VERSION 5.7 ;
  NOWIREEXTENSIONATPIN ON ;
  DIVIDERCHAR "/" ;
  BUSBITCHARS "[]" ;
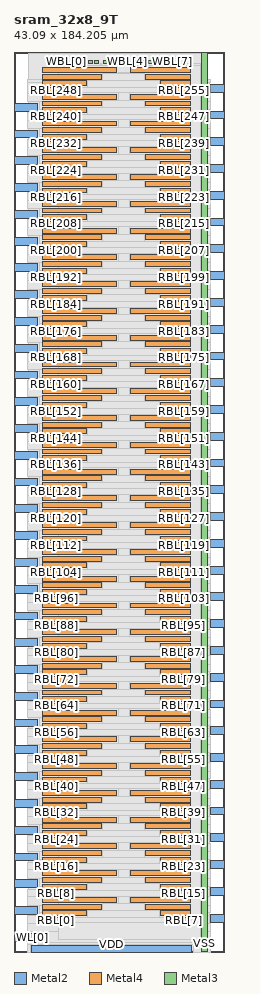
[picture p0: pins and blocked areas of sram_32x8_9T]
MACRO sram_32x8_9T
  CLASS BLOCK ;
  FOREIGN sram_32x8_9T ;
  ORIGIN -1.165 1.305 ;
  SIZE 43.090 BY 184.205 ;
  PIN A[0]
    PORT
      LAYER Metal2 ;
        RECT 41.420 4.820 44.255 6.415 ;
    END
  END A[0]
  PIN A[1]
    PORT
      LAYER Metal2 ;
        RECT 41.420 10.300 44.255 11.895 ;
    END
  END A[1]
  PIN A[2]
    PORT
      LAYER Metal2 ;
        RECT 41.420 15.780 44.255 17.375 ;
    END
  END A[2]
  PIN A[3]
    PORT
      LAYER Metal2 ;
        RECT 41.420 21.260 44.255 22.855 ;
    END
  END A[3]
  PIN A[4]
    PORT
      LAYER Metal2 ;
        RECT 41.420 26.740 44.255 28.335 ;
    END
  END A[4]
  PIN A[5]
    PORT
      LAYER Metal2 ;
        RECT 41.420 32.220 44.255 33.815 ;
    END
  END A[5]
  PIN A[6]
    PORT
      LAYER Metal2 ;
        RECT 41.420 37.700 44.255 39.295 ;
    END
  END A[6]
  PIN A[7]
    PORT
      LAYER Metal2 ;
        RECT 41.420 43.180 44.255 44.775 ;
    END
  END A[7]
  PIN A[8]
    PORT
      LAYER Metal2 ;
        RECT 41.420 48.660 44.255 50.255 ;
    END
  END A[8]
  PIN A[9]
    PORT
      LAYER Metal2 ;
        RECT 41.420 54.140 44.255 55.735 ;
    END
  END A[9]
  PIN A[10]
    PORT
      LAYER Metal2 ;
        RECT 41.420 59.620 44.255 61.215 ;
    END
  END A[10]
  PIN A[11]
    PORT
      LAYER Metal2 ;
        RECT 41.420 65.100 44.255 66.695 ;
    END
  END A[11]
  PIN A[12]
    PORT
      LAYER Metal2 ;
        RECT 41.420 70.580 44.255 72.175 ;
    END
  END A[12]
  PIN A[13]
    PORT
      LAYER Metal2 ;
        RECT 41.420 76.060 44.255 77.655 ;
    END
  END A[13]
  PIN A[14]
    PORT
      LAYER Metal2 ;
        RECT 41.420 81.540 44.255 83.135 ;
    END
  END A[14]
  PIN A[15]
    PORT
      LAYER Metal2 ;
        RECT 41.420 87.020 44.255 88.615 ;
    END
  END A[15]
  PIN A[16]
    PORT
      LAYER Metal2 ;
        RECT 41.420 92.500 44.255 94.095 ;
    END
  END A[16]
  PIN A[17]
    PORT
      LAYER Metal2 ;
        RECT 41.420 97.980 44.255 99.575 ;
    END
  END A[17]
  PIN A[18]
    PORT
      LAYER Metal2 ;
        RECT 41.420 103.460 44.255 105.055 ;
    END
  END A[18]
  PIN A[19]
    PORT
      LAYER Metal2 ;
        RECT 41.420 108.940 44.255 110.535 ;
    END
  END A[19]
  PIN A[20]
    PORT
      LAYER Metal2 ;
        RECT 41.420 114.420 44.255 116.015 ;
    END
  END A[20]
  PIN A[21]
    PORT
      LAYER Metal2 ;
        RECT 41.420 119.900 44.255 121.495 ;
    END
  END A[21]
  PIN A[22]
    PORT
      LAYER Metal2 ;
        RECT 41.420 125.380 44.255 126.975 ;
    END
  END A[22]
  PIN A[23]
    PORT
      LAYER Metal2 ;
        RECT 41.420 130.860 44.255 132.455 ;
    END
  END A[23]
  PIN A[24]
    PORT
      LAYER Metal2 ;
        RECT 41.420 136.340 44.255 137.935 ;
    END
  END A[24]
  PIN A[25]
    PORT
      LAYER Metal2 ;
        RECT 41.420 141.820 44.255 143.415 ;
    END
  END A[25]
  PIN A[26]
    PORT
      LAYER Metal2 ;
        RECT 41.420 147.300 44.255 148.895 ;
    END
  END A[26]
  PIN A[27]
    PORT
      LAYER Metal2 ;
        RECT 41.420 152.780 44.255 154.375 ;
    END
  END A[27]
  PIN A[28]
    PORT
      LAYER Metal2 ;
        RECT 41.420 158.260 44.255 159.855 ;
    END
  END A[28]
  PIN A[29]
    PORT
      LAYER Metal2 ;
        RECT 41.420 163.740 44.255 165.335 ;
    END
  END A[29]
  PIN A[30]
    PORT
      LAYER Metal2 ;
        RECT 41.420 169.220 44.255 170.815 ;
    END
  END A[30]
  PIN A[31]
    PORT
      LAYER Metal2 ;
        RECT 41.420 174.700 44.255 176.295 ;
    END
  END A[31]
  PIN RBL[0]
    ANTENNADIFFAREA 0.511400 ;
    PORT
      LAYER Metal4 ;
        RECT 7.045 4.730 12.555 5.730 ;
    END
  END RBL[0]
  PIN RBL[1]
    ANTENNADIFFAREA 0.511400 ;
    PORT
      LAYER Metal4 ;
        RECT 7.045 6.100 15.955 7.100 ;
    END
  END RBL[1]
  PIN RBL[2]
    ANTENNADIFFAREA 0.511400 ;
    PORT
      LAYER Metal4 ;
        RECT 7.045 7.470 19.065 8.470 ;
    END
  END RBL[2]
  PIN RBL[3]
    ANTENNADIFFAREA 0.511400 ;
    PORT
      LAYER Metal4 ;
        RECT 7.045 8.840 22.175 9.840 ;
    END
  END RBL[3]
  PIN RBL[4]
    ANTENNADIFFAREA 0.511400 ;
    PORT
      LAYER Metal4 ;
        RECT 25.005 8.840 37.380 9.840 ;
    END
  END RBL[4]
  PIN RBL[5]
    ANTENNADIFFAREA 0.511400 ;
    PORT
      LAYER Metal4 ;
        RECT 28.115 7.470 37.380 8.470 ;
    END
  END RBL[5]
  PIN RBL[6]
    ANTENNADIFFAREA 0.511400 ;
    PORT
      LAYER Metal4 ;
        RECT 31.225 6.100 37.380 7.100 ;
    END
  END RBL[6]
  PIN RBL[7]
    ANTENNADIFFAREA 0.511400 ;
    PORT
      LAYER Metal4 ;
        RECT 34.335 4.730 37.380 5.730 ;
    END
  END RBL[7]
  PIN RBL[8]
    ANTENNADIFFAREA 0.511400 ;
    PORT
      LAYER Metal4 ;
        RECT 7.045 10.210 12.555 11.210 ;
    END
  END RBL[8]
  PIN RBL[9]
    ANTENNADIFFAREA 0.511400 ;
    PORT
      LAYER Metal4 ;
        RECT 7.045 11.580 15.955 12.580 ;
    END
  END RBL[9]
  PIN RBL[10]
    ANTENNADIFFAREA 0.511400 ;
    PORT
      LAYER Metal4 ;
        RECT 7.045 12.950 19.065 13.950 ;
    END
  END RBL[10]
  PIN RBL[11]
    ANTENNADIFFAREA 0.511400 ;
    PORT
      LAYER Metal4 ;
        RECT 7.045 14.320 22.175 15.320 ;
    END
  END RBL[11]
  PIN RBL[12]
    ANTENNADIFFAREA 0.511400 ;
    PORT
      LAYER Metal4 ;
        RECT 25.005 14.320 37.380 15.320 ;
    END
  END RBL[12]
  PIN RBL[13]
    ANTENNADIFFAREA 0.511400 ;
    PORT
      LAYER Metal4 ;
        RECT 28.115 12.950 37.380 13.950 ;
    END
  END RBL[13]
  PIN RBL[14]
    ANTENNADIFFAREA 0.511400 ;
    PORT
      LAYER Metal4 ;
        RECT 31.225 11.580 37.380 12.580 ;
    END
  END RBL[14]
  PIN RBL[15]
    ANTENNADIFFAREA 0.511400 ;
    PORT
      LAYER Metal4 ;
        RECT 34.335 10.210 37.380 11.210 ;
    END
  END RBL[15]
  PIN RBL[16]
    ANTENNADIFFAREA 0.511400 ;
    PORT
      LAYER Metal4 ;
        RECT 7.045 15.690 12.555 16.690 ;
    END
  END RBL[16]
  PIN RBL[17]
    ANTENNADIFFAREA 0.511400 ;
    PORT
      LAYER Metal4 ;
        RECT 7.045 17.060 15.955 18.060 ;
    END
  END RBL[17]
  PIN RBL[18]
    ANTENNADIFFAREA 0.511400 ;
    PORT
      LAYER Metal4 ;
        RECT 7.045 18.430 19.065 19.430 ;
    END
  END RBL[18]
  PIN RBL[19]
    ANTENNADIFFAREA 0.511400 ;
    PORT
      LAYER Metal4 ;
        RECT 7.045 19.800 22.175 20.800 ;
    END
  END RBL[19]
  PIN RBL[20]
    ANTENNADIFFAREA 0.511400 ;
    PORT
      LAYER Metal4 ;
        RECT 25.005 19.800 37.380 20.800 ;
    END
  END RBL[20]
  PIN RBL[21]
    ANTENNADIFFAREA 0.511400 ;
    PORT
      LAYER Metal4 ;
        RECT 28.115 18.430 37.380 19.430 ;
    END
  END RBL[21]
  PIN RBL[22]
    ANTENNADIFFAREA 0.511400 ;
    PORT
      LAYER Metal4 ;
        RECT 31.225 17.060 37.380 18.060 ;
    END
  END RBL[22]
  PIN RBL[23]
    ANTENNADIFFAREA 0.511400 ;
    PORT
      LAYER Metal4 ;
        RECT 34.335 15.690 37.380 16.690 ;
    END
  END RBL[23]
  PIN RBL[24]
    ANTENNADIFFAREA 0.511400 ;
    PORT
      LAYER Metal4 ;
        RECT 7.045 21.170 12.555 22.170 ;
    END
  END RBL[24]
  PIN RBL[25]
    ANTENNADIFFAREA 0.511400 ;
    PORT
      LAYER Metal4 ;
        RECT 7.045 22.540 15.955 23.540 ;
    END
  END RBL[25]
  PIN RBL[26]
    ANTENNADIFFAREA 0.511400 ;
    PORT
      LAYER Metal4 ;
        RECT 7.045 23.910 19.065 24.910 ;
    END
  END RBL[26]
  PIN RBL[27]
    ANTENNADIFFAREA 0.511400 ;
    PORT
      LAYER Metal4 ;
        RECT 7.045 25.280 22.175 26.280 ;
    END
  END RBL[27]
  PIN RBL[28]
    ANTENNADIFFAREA 0.511400 ;
    PORT
      LAYER Metal4 ;
        RECT 25.005 25.280 37.380 26.280 ;
    END
  END RBL[28]
  PIN RBL[29]
    ANTENNADIFFAREA 0.511400 ;
    PORT
      LAYER Metal4 ;
        RECT 28.115 23.910 37.380 24.910 ;
    END
  END RBL[29]
  PIN RBL[30]
    ANTENNADIFFAREA 0.511400 ;
    PORT
      LAYER Metal4 ;
        RECT 31.225 22.540 37.380 23.540 ;
    END
  END RBL[30]
  PIN RBL[31]
    ANTENNADIFFAREA 0.511400 ;
    PORT
      LAYER Metal4 ;
        RECT 34.335 21.170 37.380 22.170 ;
    END
  END RBL[31]
  PIN RBL[32]
    ANTENNADIFFAREA 0.511400 ;
    PORT
      LAYER Metal4 ;
        RECT 7.045 26.650 12.555 27.650 ;
    END
  END RBL[32]
  PIN RBL[33]
    ANTENNADIFFAREA 0.511400 ;
    PORT
      LAYER Metal4 ;
        RECT 7.045 28.020 15.955 29.020 ;
    END
  END RBL[33]
  PIN RBL[34]
    ANTENNADIFFAREA 0.511400 ;
    PORT
      LAYER Metal4 ;
        RECT 7.045 29.390 19.065 30.390 ;
    END
  END RBL[34]
  PIN RBL[35]
    ANTENNADIFFAREA 0.511400 ;
    PORT
      LAYER Metal4 ;
        RECT 7.045 30.760 22.175 31.760 ;
    END
  END RBL[35]
  PIN RBL[36]
    ANTENNADIFFAREA 0.511400 ;
    PORT
      LAYER Metal4 ;
        RECT 25.005 30.760 37.380 31.760 ;
    END
  END RBL[36]
  PIN RBL[37]
    ANTENNADIFFAREA 0.511400 ;
    PORT
      LAYER Metal4 ;
        RECT 28.115 29.390 37.380 30.390 ;
    END
  END RBL[37]
  PIN RBL[38]
    ANTENNADIFFAREA 0.511400 ;
    PORT
      LAYER Metal4 ;
        RECT 31.225 28.020 37.380 29.020 ;
    END
  END RBL[38]
  PIN RBL[39]
    ANTENNADIFFAREA 0.511400 ;
    PORT
      LAYER Metal4 ;
        RECT 34.335 26.650 37.380 27.650 ;
    END
  END RBL[39]
  PIN RBL[40]
    ANTENNADIFFAREA 0.511400 ;
    PORT
      LAYER Metal4 ;
        RECT 7.045 32.130 12.555 33.130 ;
    END
  END RBL[40]
  PIN RBL[41]
    ANTENNADIFFAREA 0.511400 ;
    PORT
      LAYER Metal4 ;
        RECT 7.045 33.500 15.955 34.500 ;
    END
  END RBL[41]
  PIN RBL[42]
    ANTENNADIFFAREA 0.511400 ;
    PORT
      LAYER Metal4 ;
        RECT 7.045 34.870 19.065 35.870 ;
    END
  END RBL[42]
  PIN RBL[43]
    ANTENNADIFFAREA 0.511400 ;
    PORT
      LAYER Metal4 ;
        RECT 7.045 36.240 22.175 37.240 ;
    END
  END RBL[43]
  PIN RBL[44]
    ANTENNADIFFAREA 0.511400 ;
    PORT
      LAYER Metal4 ;
        RECT 25.005 36.240 37.380 37.240 ;
    END
  END RBL[44]
  PIN RBL[45]
    ANTENNADIFFAREA 0.511400 ;
    PORT
      LAYER Metal4 ;
        RECT 28.115 34.870 37.380 35.870 ;
    END
  END RBL[45]
  PIN RBL[46]
    ANTENNADIFFAREA 0.511400 ;
    PORT
      LAYER Metal4 ;
        RECT 31.225 33.500 37.380 34.500 ;
    END
  END RBL[46]
  PIN RBL[47]
    ANTENNADIFFAREA 0.511400 ;
    PORT
      LAYER Metal4 ;
        RECT 34.335 32.130 37.380 33.130 ;
    END
  END RBL[47]
  PIN RBL[48]
    ANTENNADIFFAREA 0.511400 ;
    PORT
      LAYER Metal4 ;
        RECT 7.045 37.610 12.555 38.610 ;
    END
  END RBL[48]
  PIN RBL[49]
    ANTENNADIFFAREA 0.511400 ;
    PORT
      LAYER Metal4 ;
        RECT 7.045 38.980 15.955 39.980 ;
    END
  END RBL[49]
  PIN RBL[50]
    ANTENNADIFFAREA 0.511400 ;
    PORT
      LAYER Metal4 ;
        RECT 7.045 40.350 19.065 41.350 ;
    END
  END RBL[50]
  PIN RBL[51]
    ANTENNADIFFAREA 0.511400 ;
    PORT
      LAYER Metal4 ;
        RECT 7.045 41.720 22.175 42.720 ;
    END
  END RBL[51]
  PIN RBL[52]
    ANTENNADIFFAREA 0.511400 ;
    PORT
      LAYER Metal4 ;
        RECT 25.005 41.720 37.380 42.720 ;
    END
  END RBL[52]
  PIN RBL[53]
    ANTENNADIFFAREA 0.511400 ;
    PORT
      LAYER Metal4 ;
        RECT 28.115 40.350 37.380 41.350 ;
    END
  END RBL[53]
  PIN RBL[54]
    ANTENNADIFFAREA 0.511400 ;
    PORT
      LAYER Metal4 ;
        RECT 31.225 38.980 37.380 39.980 ;
    END
  END RBL[54]
  PIN RBL[55]
    ANTENNADIFFAREA 0.511400 ;
    PORT
      LAYER Metal4 ;
        RECT 34.335 37.610 37.380 38.610 ;
    END
  END RBL[55]
  PIN RBL[56]
    ANTENNADIFFAREA 0.511400 ;
    PORT
      LAYER Metal4 ;
        RECT 7.045 43.090 12.555 44.090 ;
    END
  END RBL[56]
  PIN RBL[57]
    ANTENNADIFFAREA 0.511400 ;
    PORT
      LAYER Metal4 ;
        RECT 7.045 44.460 15.955 45.460 ;
    END
  END RBL[57]
  PIN RBL[58]
    ANTENNADIFFAREA 0.511400 ;
    PORT
      LAYER Metal4 ;
        RECT 7.045 45.830 19.065 46.830 ;
    END
  END RBL[58]
  PIN RBL[59]
    ANTENNADIFFAREA 0.511400 ;
    PORT
      LAYER Metal4 ;
        RECT 7.045 47.200 22.175 48.200 ;
    END
  END RBL[59]
  PIN RBL[60]
    ANTENNADIFFAREA 0.511400 ;
    PORT
      LAYER Metal4 ;
        RECT 25.005 47.200 37.380 48.200 ;
    END
  END RBL[60]
  PIN RBL[61]
    ANTENNADIFFAREA 0.511400 ;
    PORT
      LAYER Metal4 ;
        RECT 28.115 45.830 37.380 46.830 ;
    END
  END RBL[61]
  PIN RBL[62]
    ANTENNADIFFAREA 0.511400 ;
    PORT
      LAYER Metal4 ;
        RECT 31.225 44.460 37.380 45.460 ;
    END
  END RBL[62]
  PIN RBL[63]
    ANTENNADIFFAREA 0.511400 ;
    PORT
      LAYER Metal4 ;
        RECT 34.335 43.090 37.380 44.090 ;
    END
  END RBL[63]
  PIN RBL[64]
    ANTENNADIFFAREA 0.511400 ;
    PORT
      LAYER Metal4 ;
        RECT 7.045 48.570 12.555 49.570 ;
    END
  END RBL[64]
  PIN RBL[65]
    ANTENNADIFFAREA 0.511400 ;
    PORT
      LAYER Metal4 ;
        RECT 7.045 49.940 15.955 50.940 ;
    END
  END RBL[65]
  PIN RBL[66]
    ANTENNADIFFAREA 0.511400 ;
    PORT
      LAYER Metal4 ;
        RECT 7.045 51.310 19.065 52.310 ;
    END
  END RBL[66]
  PIN RBL[67]
    ANTENNADIFFAREA 0.511400 ;
    PORT
      LAYER Metal4 ;
        RECT 7.045 52.680 22.175 53.680 ;
    END
  END RBL[67]
  PIN RBL[68]
    ANTENNADIFFAREA 0.511400 ;
    PORT
      LAYER Metal4 ;
        RECT 25.005 52.680 37.380 53.680 ;
    END
  END RBL[68]
  PIN RBL[69]
    ANTENNADIFFAREA 0.511400 ;
    PORT
      LAYER Metal4 ;
        RECT 28.115 51.310 37.380 52.310 ;
    END
  END RBL[69]
  PIN RBL[70]
    ANTENNADIFFAREA 0.511400 ;
    PORT
      LAYER Metal4 ;
        RECT 31.225 49.940 37.380 50.940 ;
    END
  END RBL[70]
  PIN RBL[71]
    ANTENNADIFFAREA 0.511400 ;
    PORT
      LAYER Metal4 ;
        RECT 34.335 48.570 37.380 49.570 ;
    END
  END RBL[71]
  PIN RBL[72]
    ANTENNADIFFAREA 0.511400 ;
    PORT
      LAYER Metal4 ;
        RECT 7.045 54.050 12.555 55.050 ;
    END
  END RBL[72]
  PIN RBL[73]
    ANTENNADIFFAREA 0.511400 ;
    PORT
      LAYER Metal4 ;
        RECT 7.045 55.420 15.955 56.420 ;
    END
  END RBL[73]
  PIN RBL[74]
    ANTENNADIFFAREA 0.511400 ;
    PORT
      LAYER Metal4 ;
        RECT 7.045 56.790 19.065 57.790 ;
    END
  END RBL[74]
  PIN RBL[75]
    ANTENNADIFFAREA 0.511400 ;
    PORT
      LAYER Metal4 ;
        RECT 7.045 58.160 22.175 59.160 ;
    END
  END RBL[75]
  PIN RBL[76]
    ANTENNADIFFAREA 0.511400 ;
    PORT
      LAYER Metal4 ;
        RECT 25.005 58.160 37.380 59.160 ;
    END
  END RBL[76]
  PIN RBL[77]
    ANTENNADIFFAREA 0.511400 ;
    PORT
      LAYER Metal4 ;
        RECT 28.115 56.790 37.380 57.790 ;
    END
  END RBL[77]
  PIN RBL[78]
    ANTENNADIFFAREA 0.511400 ;
    PORT
      LAYER Metal4 ;
        RECT 31.225 55.420 37.380 56.420 ;
    END
  END RBL[78]
  PIN RBL[79]
    ANTENNADIFFAREA 0.511400 ;
    PORT
      LAYER Metal4 ;
        RECT 34.335 54.050 37.380 55.050 ;
    END
  END RBL[79]
  PIN RBL[80]
    ANTENNADIFFAREA 0.511400 ;
    PORT
      LAYER Metal4 ;
        RECT 7.045 59.530 12.555 60.530 ;
    END
  END RBL[80]
  PIN RBL[81]
    ANTENNADIFFAREA 0.511400 ;
    PORT
      LAYER Metal4 ;
        RECT 7.045 60.900 15.955 61.900 ;
    END
  END RBL[81]
  PIN RBL[82]
    ANTENNADIFFAREA 0.511400 ;
    PORT
      LAYER Metal4 ;
        RECT 7.045 62.270 19.065 63.270 ;
    END
  END RBL[82]
  PIN RBL[83]
    ANTENNADIFFAREA 0.511400 ;
    PORT
      LAYER Metal4 ;
        RECT 7.045 63.640 22.175 64.640 ;
    END
  END RBL[83]
  PIN RBL[84]
    ANTENNADIFFAREA 0.511400 ;
    PORT
      LAYER Metal4 ;
        RECT 25.005 63.640 37.380 64.640 ;
    END
  END RBL[84]
  PIN RBL[85]
    ANTENNADIFFAREA 0.511400 ;
    PORT
      LAYER Metal4 ;
        RECT 28.115 62.270 37.380 63.270 ;
    END
  END RBL[85]
  PIN RBL[86]
    ANTENNADIFFAREA 0.511400 ;
    PORT
      LAYER Metal4 ;
        RECT 31.225 60.900 37.380 61.900 ;
    END
  END RBL[86]
  PIN RBL[87]
    ANTENNADIFFAREA 0.511400 ;
    PORT
      LAYER Metal4 ;
        RECT 34.335 59.530 37.380 60.530 ;
    END
  END RBL[87]
  PIN RBL[88]
    ANTENNADIFFAREA 0.511400 ;
    PORT
      LAYER Metal4 ;
        RECT 7.045 65.010 12.555 66.010 ;
    END
  END RBL[88]
  PIN RBL[89]
    ANTENNADIFFAREA 0.511400 ;
    PORT
      LAYER Metal4 ;
        RECT 7.045 66.380 15.955 67.380 ;
    END
  END RBL[89]
  PIN RBL[90]
    ANTENNADIFFAREA 0.511400 ;
    PORT
      LAYER Metal4 ;
        RECT 7.045 67.750 19.065 68.750 ;
    END
  END RBL[90]
  PIN RBL[91]
    ANTENNADIFFAREA 0.511400 ;
    PORT
      LAYER Metal4 ;
        RECT 7.045 69.120 22.175 70.120 ;
    END
  END RBL[91]
  PIN RBL[92]
    ANTENNADIFFAREA 0.511400 ;
    PORT
      LAYER Metal4 ;
        RECT 25.005 69.120 37.380 70.120 ;
    END
  END RBL[92]
  PIN RBL[93]
    ANTENNADIFFAREA 0.511400 ;
    PORT
      LAYER Metal4 ;
        RECT 28.115 67.750 37.380 68.750 ;
    END
  END RBL[93]
  PIN RBL[94]
    ANTENNADIFFAREA 0.511400 ;
    PORT
      LAYER Metal4 ;
        RECT 31.225 66.380 37.380 67.380 ;
    END
  END RBL[94]
  PIN RBL[95]
    ANTENNADIFFAREA 0.511400 ;
    PORT
      LAYER Metal4 ;
        RECT 34.335 65.010 37.380 66.010 ;
    END
  END RBL[95]
  PIN RBL[96]
    ANTENNADIFFAREA 0.511400 ;
    PORT
      LAYER Metal4 ;
        RECT 7.045 70.490 12.555 71.490 ;
    END
  END RBL[96]
  PIN RBL[97]
    ANTENNADIFFAREA 0.511400 ;
    PORT
      LAYER Metal4 ;
        RECT 7.045 71.860 15.955 72.860 ;
    END
  END RBL[97]
  PIN RBL[98]
    ANTENNADIFFAREA 0.511400 ;
    PORT
      LAYER Metal4 ;
        RECT 7.045 73.230 19.065 74.230 ;
    END
  END RBL[98]
  PIN RBL[99]
    ANTENNADIFFAREA 0.511400 ;
    PORT
      LAYER Metal4 ;
        RECT 7.045 74.600 22.175 75.600 ;
    END
  END RBL[99]
  PIN RBL[100]
    ANTENNADIFFAREA 0.511400 ;
    PORT
      LAYER Metal4 ;
        RECT 25.005 74.600 37.380 75.600 ;
    END
  END RBL[100]
  PIN RBL[101]
    ANTENNADIFFAREA 0.511400 ;
    PORT
      LAYER Metal4 ;
        RECT 28.115 73.230 37.380 74.230 ;
    END
  END RBL[101]
  PIN RBL[102]
    ANTENNADIFFAREA 0.511400 ;
    PORT
      LAYER Metal4 ;
        RECT 31.225 71.860 37.380 72.860 ;
    END
  END RBL[102]
  PIN RBL[103]
    ANTENNADIFFAREA 0.511400 ;
    PORT
      LAYER Metal4 ;
        RECT 34.335 70.490 37.380 71.490 ;
    END
  END RBL[103]
  PIN RBL[104]
    ANTENNADIFFAREA 0.511400 ;
    PORT
      LAYER Metal4 ;
        RECT 7.045 75.970 12.555 76.970 ;
    END
  END RBL[104]
  PIN RBL[105]
    ANTENNADIFFAREA 0.511400 ;
    PORT
      LAYER Metal4 ;
        RECT 7.045 77.340 15.955 78.340 ;
    END
  END RBL[105]
  PIN RBL[106]
    ANTENNADIFFAREA 0.511400 ;
    PORT
      LAYER Metal4 ;
        RECT 7.045 78.710 19.065 79.710 ;
    END
  END RBL[106]
  PIN RBL[107]
    ANTENNADIFFAREA 0.511400 ;
    PORT
      LAYER Metal4 ;
        RECT 7.045 80.080 22.175 81.080 ;
    END
  END RBL[107]
  PIN RBL[108]
    ANTENNADIFFAREA 0.511400 ;
    PORT
      LAYER Metal4 ;
        RECT 25.005 80.080 37.380 81.080 ;
    END
  END RBL[108]
  PIN RBL[109]
    ANTENNADIFFAREA 0.511400 ;
    PORT
      LAYER Metal4 ;
        RECT 28.115 78.710 37.380 79.710 ;
    END
  END RBL[109]
  PIN RBL[110]
    ANTENNADIFFAREA 0.511400 ;
    PORT
      LAYER Metal4 ;
        RECT 31.225 77.340 37.380 78.340 ;
    END
  END RBL[110]
  PIN RBL[111]
    ANTENNADIFFAREA 0.511400 ;
    PORT
      LAYER Metal4 ;
        RECT 34.335 75.970 37.380 76.970 ;
    END
  END RBL[111]
  PIN RBL[112]
    ANTENNADIFFAREA 0.511400 ;
    PORT
      LAYER Metal4 ;
        RECT 7.045 81.450 12.555 82.450 ;
    END
  END RBL[112]
  PIN RBL[113]
    ANTENNADIFFAREA 0.511400 ;
    PORT
      LAYER Metal4 ;
        RECT 7.045 82.820 15.955 83.820 ;
    END
  END RBL[113]
  PIN RBL[114]
    ANTENNADIFFAREA 0.511400 ;
    PORT
      LAYER Metal4 ;
        RECT 7.045 84.190 19.065 85.190 ;
    END
  END RBL[114]
  PIN RBL[115]
    ANTENNADIFFAREA 0.511400 ;
    PORT
      LAYER Metal4 ;
        RECT 7.045 85.560 22.175 86.560 ;
    END
  END RBL[115]
  PIN RBL[116]
    ANTENNADIFFAREA 0.511400 ;
    PORT
      LAYER Metal4 ;
        RECT 25.005 85.560 37.380 86.560 ;
    END
  END RBL[116]
  PIN RBL[117]
    ANTENNADIFFAREA 0.511400 ;
    PORT
      LAYER Metal4 ;
        RECT 28.115 84.190 37.380 85.190 ;
    END
  END RBL[117]
  PIN RBL[118]
    ANTENNADIFFAREA 0.511400 ;
    PORT
      LAYER Metal4 ;
        RECT 31.225 82.820 37.380 83.820 ;
    END
  END RBL[118]
  PIN RBL[119]
    ANTENNADIFFAREA 0.511400 ;
    PORT
      LAYER Metal4 ;
        RECT 34.335 81.450 37.380 82.450 ;
    END
  END RBL[119]
  PIN RBL[120]
    ANTENNADIFFAREA 0.511400 ;
    PORT
      LAYER Metal4 ;
        RECT 7.045 86.930 12.555 87.930 ;
    END
  END RBL[120]
  PIN RBL[121]
    ANTENNADIFFAREA 0.511400 ;
    PORT
      LAYER Metal4 ;
        RECT 7.045 88.300 15.955 89.300 ;
    END
  END RBL[121]
  PIN RBL[122]
    ANTENNADIFFAREA 0.511400 ;
    PORT
      LAYER Metal4 ;
        RECT 7.045 89.670 19.065 90.670 ;
    END
  END RBL[122]
  PIN RBL[123]
    ANTENNADIFFAREA 0.511400 ;
    PORT
      LAYER Metal4 ;
        RECT 7.045 91.040 22.175 92.040 ;
    END
  END RBL[123]
  PIN RBL[124]
    ANTENNADIFFAREA 0.511400 ;
    PORT
      LAYER Metal4 ;
        RECT 25.005 91.040 37.380 92.040 ;
    END
  END RBL[124]
  PIN RBL[125]
    ANTENNADIFFAREA 0.511400 ;
    PORT
      LAYER Metal4 ;
        RECT 28.115 89.670 37.380 90.670 ;
    END
  END RBL[125]
  PIN RBL[126]
    ANTENNADIFFAREA 0.511400 ;
    PORT
      LAYER Metal4 ;
        RECT 31.225 88.300 37.380 89.300 ;
    END
  END RBL[126]
  PIN RBL[127]
    ANTENNADIFFAREA 0.511400 ;
    PORT
      LAYER Metal4 ;
        RECT 34.335 86.930 37.380 87.930 ;
    END
  END RBL[127]
  PIN RBL[128]
    ANTENNADIFFAREA 0.511400 ;
    PORT
      LAYER Metal4 ;
        RECT 7.045 92.410 12.555 93.410 ;
    END
  END RBL[128]
  PIN RBL[129]
    ANTENNADIFFAREA 0.511400 ;
    PORT
      LAYER Metal4 ;
        RECT 7.045 93.780 15.955 94.780 ;
    END
  END RBL[129]
  PIN RBL[130]
    ANTENNADIFFAREA 0.511400 ;
    PORT
      LAYER Metal4 ;
        RECT 7.045 95.150 19.065 96.150 ;
    END
  END RBL[130]
  PIN RBL[131]
    ANTENNADIFFAREA 0.511400 ;
    PORT
      LAYER Metal4 ;
        RECT 7.045 96.520 22.175 97.520 ;
    END
  END RBL[131]
  PIN RBL[132]
    ANTENNADIFFAREA 0.511400 ;
    PORT
      LAYER Metal4 ;
        RECT 25.005 96.520 37.380 97.520 ;
    END
  END RBL[132]
  PIN RBL[133]
    ANTENNADIFFAREA 0.511400 ;
    PORT
      LAYER Metal4 ;
        RECT 28.115 95.150 37.380 96.150 ;
    END
  END RBL[133]
  PIN RBL[134]
    ANTENNADIFFAREA 0.511400 ;
    PORT
      LAYER Metal4 ;
        RECT 31.225 93.780 37.380 94.780 ;
    END
  END RBL[134]
  PIN RBL[135]
    ANTENNADIFFAREA 0.511400 ;
    PORT
      LAYER Metal4 ;
        RECT 34.335 92.410 37.380 93.410 ;
    END
  END RBL[135]
  PIN RBL[136]
    ANTENNADIFFAREA 0.511400 ;
    PORT
      LAYER Metal4 ;
        RECT 7.045 97.890 12.555 98.890 ;
    END
  END RBL[136]
  PIN RBL[137]
    ANTENNADIFFAREA 0.511400 ;
    PORT
      LAYER Metal4 ;
        RECT 7.045 99.260 15.955 100.260 ;
    END
  END RBL[137]
  PIN RBL[138]
    ANTENNADIFFAREA 0.511400 ;
    PORT
      LAYER Metal4 ;
        RECT 7.045 100.630 19.065 101.630 ;
    END
  END RBL[138]
  PIN RBL[139]
    ANTENNADIFFAREA 0.511400 ;
    PORT
      LAYER Metal4 ;
        RECT 7.045 102.000 22.175 103.000 ;
    END
  END RBL[139]
  PIN RBL[140]
    ANTENNADIFFAREA 0.511400 ;
    PORT
      LAYER Metal4 ;
        RECT 25.005 102.000 37.380 103.000 ;
    END
  END RBL[140]
  PIN RBL[141]
    ANTENNADIFFAREA 0.511400 ;
    PORT
      LAYER Metal4 ;
        RECT 28.115 100.630 37.380 101.630 ;
    END
  END RBL[141]
  PIN RBL[142]
    ANTENNADIFFAREA 0.511400 ;
    PORT
      LAYER Metal4 ;
        RECT 31.225 99.260 37.380 100.260 ;
    END
  END RBL[142]
  PIN RBL[143]
    ANTENNADIFFAREA 0.511400 ;
    PORT
      LAYER Metal4 ;
        RECT 34.335 97.890 37.380 98.890 ;
    END
  END RBL[143]
  PIN RBL[144]
    ANTENNADIFFAREA 0.511400 ;
    PORT
      LAYER Metal4 ;
        RECT 7.045 103.370 12.555 104.370 ;
    END
  END RBL[144]
  PIN RBL[145]
    ANTENNADIFFAREA 0.511400 ;
    PORT
      LAYER Metal4 ;
        RECT 7.045 104.740 15.955 105.740 ;
    END
  END RBL[145]
  PIN RBL[146]
    ANTENNADIFFAREA 0.511400 ;
    PORT
      LAYER Metal4 ;
        RECT 7.045 106.110 19.065 107.110 ;
    END
  END RBL[146]
  PIN RBL[147]
    ANTENNADIFFAREA 0.511400 ;
    PORT
      LAYER Metal4 ;
        RECT 7.045 107.480 22.175 108.480 ;
    END
  END RBL[147]
  PIN RBL[148]
    ANTENNADIFFAREA 0.511400 ;
    PORT
      LAYER Metal4 ;
        RECT 25.005 107.480 37.380 108.480 ;
    END
  END RBL[148]
  PIN RBL[149]
    ANTENNADIFFAREA 0.511400 ;
    PORT
      LAYER Metal4 ;
        RECT 28.115 106.110 37.380 107.110 ;
    END
  END RBL[149]
  PIN RBL[150]
    ANTENNADIFFAREA 0.511400 ;
    PORT
      LAYER Metal4 ;
        RECT 31.225 104.740 37.380 105.740 ;
    END
  END RBL[150]
  PIN RBL[151]
    ANTENNADIFFAREA 0.511400 ;
    PORT
      LAYER Metal4 ;
        RECT 34.335 103.370 37.380 104.370 ;
    END
  END RBL[151]
  PIN RBL[152]
    ANTENNADIFFAREA 0.511400 ;
    PORT
      LAYER Metal4 ;
        RECT 7.045 108.850 12.555 109.850 ;
    END
  END RBL[152]
  PIN RBL[153]
    ANTENNADIFFAREA 0.511400 ;
    PORT
      LAYER Metal4 ;
        RECT 7.045 110.220 15.955 111.220 ;
    END
  END RBL[153]
  PIN RBL[154]
    ANTENNADIFFAREA 0.511400 ;
    PORT
      LAYER Metal4 ;
        RECT 7.045 111.590 19.065 112.590 ;
    END
  END RBL[154]
  PIN RBL[155]
    ANTENNADIFFAREA 0.511400 ;
    PORT
      LAYER Metal4 ;
        RECT 7.045 112.960 22.175 113.960 ;
    END
  END RBL[155]
  PIN RBL[156]
    ANTENNADIFFAREA 0.511400 ;
    PORT
      LAYER Metal4 ;
        RECT 25.005 112.960 37.380 113.960 ;
    END
  END RBL[156]
  PIN RBL[157]
    ANTENNADIFFAREA 0.511400 ;
    PORT
      LAYER Metal4 ;
        RECT 28.115 111.590 37.380 112.590 ;
    END
  END RBL[157]
  PIN RBL[158]
    ANTENNADIFFAREA 0.511400 ;
    PORT
      LAYER Metal4 ;
        RECT 31.225 110.220 37.380 111.220 ;
    END
  END RBL[158]
  PIN RBL[159]
    ANTENNADIFFAREA 0.511400 ;
    PORT
      LAYER Metal4 ;
        RECT 34.335 108.850 37.380 109.850 ;
    END
  END RBL[159]
  PIN RBL[160]
    ANTENNADIFFAREA 0.511400 ;
    PORT
      LAYER Metal4 ;
        RECT 7.045 114.330 12.555 115.330 ;
    END
  END RBL[160]
  PIN RBL[161]
    ANTENNADIFFAREA 0.511400 ;
    PORT
      LAYER Metal4 ;
        RECT 7.045 115.700 15.955 116.700 ;
    END
  END RBL[161]
  PIN RBL[162]
    ANTENNADIFFAREA 0.511400 ;
    PORT
      LAYER Metal4 ;
        RECT 7.045 117.070 19.065 118.070 ;
    END
  END RBL[162]
  PIN RBL[163]
    ANTENNADIFFAREA 0.511400 ;
    PORT
      LAYER Metal4 ;
        RECT 7.045 118.440 22.175 119.440 ;
    END
  END RBL[163]
  PIN RBL[164]
    ANTENNADIFFAREA 0.511400 ;
    PORT
      LAYER Metal4 ;
        RECT 25.005 118.440 37.380 119.440 ;
    END
  END RBL[164]
  PIN RBL[165]
    ANTENNADIFFAREA 0.511400 ;
    PORT
      LAYER Metal4 ;
        RECT 28.115 117.070 37.380 118.070 ;
    END
  END RBL[165]
  PIN RBL[166]
    ANTENNADIFFAREA 0.511400 ;
    PORT
      LAYER Metal4 ;
        RECT 31.225 115.700 37.380 116.700 ;
    END
  END RBL[166]
  PIN RBL[167]
    ANTENNADIFFAREA 0.511400 ;
    PORT
      LAYER Metal4 ;
        RECT 34.335 114.330 37.380 115.330 ;
    END
  END RBL[167]
  PIN RBL[168]
    ANTENNADIFFAREA 0.511400 ;
    PORT
      LAYER Metal4 ;
        RECT 7.045 119.810 12.555 120.810 ;
    END
  END RBL[168]
  PIN RBL[169]
    ANTENNADIFFAREA 0.511400 ;
    PORT
      LAYER Metal4 ;
        RECT 7.045 121.180 15.955 122.180 ;
    END
  END RBL[169]
  PIN RBL[170]
    ANTENNADIFFAREA 0.511400 ;
    PORT
      LAYER Metal4 ;
        RECT 7.045 122.550 19.065 123.550 ;
    END
  END RBL[170]
  PIN RBL[171]
    ANTENNADIFFAREA 0.511400 ;
    PORT
      LAYER Metal4 ;
        RECT 7.045 123.920 22.175 124.920 ;
    END
  END RBL[171]
  PIN RBL[172]
    ANTENNADIFFAREA 0.511400 ;
    PORT
      LAYER Metal4 ;
        RECT 25.005 123.920 37.380 124.920 ;
    END
  END RBL[172]
  PIN RBL[173]
    ANTENNADIFFAREA 0.511400 ;
    PORT
      LAYER Metal4 ;
        RECT 28.115 122.550 37.380 123.550 ;
    END
  END RBL[173]
  PIN RBL[174]
    ANTENNADIFFAREA 0.511400 ;
    PORT
      LAYER Metal4 ;
        RECT 31.225 121.180 37.380 122.180 ;
    END
  END RBL[174]
  PIN RBL[175]
    ANTENNADIFFAREA 0.511400 ;
    PORT
      LAYER Metal4 ;
        RECT 34.335 119.810 37.380 120.810 ;
    END
  END RBL[175]
  PIN RBL[176]
    ANTENNADIFFAREA 0.511400 ;
    PORT
      LAYER Metal4 ;
        RECT 7.045 125.290 12.555 126.290 ;
    END
  END RBL[176]
  PIN RBL[177]
    ANTENNADIFFAREA 0.511400 ;
    PORT
      LAYER Metal4 ;
        RECT 7.045 126.660 15.955 127.660 ;
    END
  END RBL[177]
  PIN RBL[178]
    ANTENNADIFFAREA 0.511400 ;
    PORT
      LAYER Metal4 ;
        RECT 7.045 128.030 19.065 129.030 ;
    END
  END RBL[178]
  PIN RBL[179]
    ANTENNADIFFAREA 0.511400 ;
    PORT
      LAYER Metal4 ;
        RECT 7.045 129.400 22.175 130.400 ;
    END
  END RBL[179]
  PIN RBL[180]
    ANTENNADIFFAREA 0.511400 ;
    PORT
      LAYER Metal4 ;
        RECT 25.005 129.400 37.380 130.400 ;
    END
  END RBL[180]
  PIN RBL[181]
    ANTENNADIFFAREA 0.511400 ;
    PORT
      LAYER Metal4 ;
        RECT 28.115 128.030 37.380 129.030 ;
    END
  END RBL[181]
  PIN RBL[182]
    ANTENNADIFFAREA 0.511400 ;
    PORT
      LAYER Metal4 ;
        RECT 31.225 126.660 37.380 127.660 ;
    END
  END RBL[182]
  PIN RBL[183]
    ANTENNADIFFAREA 0.511400 ;
    PORT
      LAYER Metal4 ;
        RECT 34.335 125.290 37.380 126.290 ;
    END
  END RBL[183]
  PIN RBL[184]
    ANTENNADIFFAREA 0.511400 ;
    PORT
      LAYER Metal4 ;
        RECT 7.045 130.770 12.555 131.770 ;
    END
  END RBL[184]
  PIN RBL[185]
    ANTENNADIFFAREA 0.511400 ;
    PORT
      LAYER Metal4 ;
        RECT 7.045 132.140 15.955 133.140 ;
    END
  END RBL[185]
  PIN RBL[186]
    ANTENNADIFFAREA 0.511400 ;
    PORT
      LAYER Metal4 ;
        RECT 7.045 133.510 19.065 134.510 ;
    END
  END RBL[186]
  PIN RBL[187]
    ANTENNADIFFAREA 0.511400 ;
    PORT
      LAYER Metal4 ;
        RECT 7.045 134.880 22.175 135.880 ;
    END
  END RBL[187]
  PIN RBL[188]
    ANTENNADIFFAREA 0.511400 ;
    PORT
      LAYER Metal4 ;
        RECT 25.005 134.880 37.380 135.880 ;
    END
  END RBL[188]
  PIN RBL[189]
    ANTENNADIFFAREA 0.511400 ;
    PORT
      LAYER Metal4 ;
        RECT 28.115 133.510 37.380 134.510 ;
    END
  END RBL[189]
  PIN RBL[190]
    ANTENNADIFFAREA 0.511400 ;
    PORT
      LAYER Metal4 ;
        RECT 31.225 132.140 37.380 133.140 ;
    END
  END RBL[190]
  PIN RBL[191]
    ANTENNADIFFAREA 0.511400 ;
    PORT
      LAYER Metal4 ;
        RECT 34.335 130.770 37.380 131.770 ;
    END
  END RBL[191]
  PIN RBL[192]
    ANTENNADIFFAREA 0.511400 ;
    PORT
      LAYER Metal4 ;
        RECT 7.045 136.250 12.555 137.250 ;
    END
  END RBL[192]
  PIN RBL[193]
    ANTENNADIFFAREA 0.511400 ;
    PORT
      LAYER Metal4 ;
        RECT 7.045 137.620 15.955 138.620 ;
    END
  END RBL[193]
  PIN RBL[194]
    ANTENNADIFFAREA 0.511400 ;
    PORT
      LAYER Metal4 ;
        RECT 7.045 138.990 19.065 139.990 ;
    END
  END RBL[194]
  PIN RBL[195]
    ANTENNADIFFAREA 0.511400 ;
    PORT
      LAYER Metal4 ;
        RECT 7.045 140.360 22.175 141.360 ;
    END
  END RBL[195]
  PIN RBL[196]
    ANTENNADIFFAREA 0.511400 ;
    PORT
      LAYER Metal4 ;
        RECT 25.005 140.360 37.380 141.360 ;
    END
  END RBL[196]
  PIN RBL[197]
    ANTENNADIFFAREA 0.511400 ;
    PORT
      LAYER Metal4 ;
        RECT 28.115 138.990 37.380 139.990 ;
    END
  END RBL[197]
  PIN RBL[198]
    ANTENNADIFFAREA 0.511400 ;
    PORT
      LAYER Metal4 ;
        RECT 31.225 137.620 37.380 138.620 ;
    END
  END RBL[198]
  PIN RBL[199]
    ANTENNADIFFAREA 0.511400 ;
    PORT
      LAYER Metal4 ;
        RECT 34.335 136.250 37.380 137.250 ;
    END
  END RBL[199]
  PIN RBL[200]
    ANTENNADIFFAREA 0.511400 ;
    PORT
      LAYER Metal4 ;
        RECT 7.045 141.730 12.555 142.730 ;
    END
  END RBL[200]
  PIN RBL[201]
    ANTENNADIFFAREA 0.511400 ;
    PORT
      LAYER Metal4 ;
        RECT 7.045 143.100 15.955 144.100 ;
    END
  END RBL[201]
  PIN RBL[202]
    ANTENNADIFFAREA 0.511400 ;
    PORT
      LAYER Metal4 ;
        RECT 7.045 144.470 19.065 145.470 ;
    END
  END RBL[202]
  PIN RBL[203]
    ANTENNADIFFAREA 0.511400 ;
    PORT
      LAYER Metal4 ;
        RECT 7.045 145.840 22.175 146.840 ;
    END
  END RBL[203]
  PIN RBL[204]
    ANTENNADIFFAREA 0.511400 ;
    PORT
      LAYER Metal4 ;
        RECT 25.005 145.840 37.380 146.840 ;
    END
  END RBL[204]
  PIN RBL[205]
    ANTENNADIFFAREA 0.511400 ;
    PORT
      LAYER Metal4 ;
        RECT 28.115 144.470 37.380 145.470 ;
    END
  END RBL[205]
  PIN RBL[206]
    ANTENNADIFFAREA 0.511400 ;
    PORT
      LAYER Metal4 ;
        RECT 31.225 143.100 37.380 144.100 ;
    END
  END RBL[206]
  PIN RBL[207]
    ANTENNADIFFAREA 0.511400 ;
    PORT
      LAYER Metal4 ;
        RECT 34.335 141.730 37.380 142.730 ;
    END
  END RBL[207]
  PIN RBL[208]
    ANTENNADIFFAREA 0.511400 ;
    PORT
      LAYER Metal4 ;
        RECT 7.045 147.210 12.555 148.210 ;
    END
  END RBL[208]
  PIN RBL[209]
    ANTENNADIFFAREA 0.511400 ;
    PORT
      LAYER Metal4 ;
        RECT 7.045 148.580 15.955 149.580 ;
    END
  END RBL[209]
  PIN RBL[210]
    ANTENNADIFFAREA 0.511400 ;
    PORT
      LAYER Metal4 ;
        RECT 7.045 149.950 19.065 150.950 ;
    END
  END RBL[210]
  PIN RBL[211]
    ANTENNADIFFAREA 0.511400 ;
    PORT
      LAYER Metal4 ;
        RECT 7.045 151.320 22.175 152.320 ;
    END
  END RBL[211]
  PIN RBL[212]
    ANTENNADIFFAREA 0.511400 ;
    PORT
      LAYER Metal4 ;
        RECT 25.005 151.320 37.380 152.320 ;
    END
  END RBL[212]
  PIN RBL[213]
    ANTENNADIFFAREA 0.511400 ;
    PORT
      LAYER Metal4 ;
        RECT 28.115 149.950 37.380 150.950 ;
    END
  END RBL[213]
  PIN RBL[214]
    ANTENNADIFFAREA 0.511400 ;
    PORT
      LAYER Metal4 ;
        RECT 31.225 148.580 37.380 149.580 ;
    END
  END RBL[214]
  PIN RBL[215]
    ANTENNADIFFAREA 0.511400 ;
    PORT
      LAYER Metal4 ;
        RECT 34.335 147.210 37.380 148.210 ;
    END
  END RBL[215]
  PIN RBL[216]
    ANTENNADIFFAREA 0.511400 ;
    PORT
      LAYER Metal4 ;
        RECT 7.045 152.690 12.555 153.690 ;
    END
  END RBL[216]
  PIN RBL[217]
    ANTENNADIFFAREA 0.511400 ;
    PORT
      LAYER Metal4 ;
        RECT 7.045 154.060 15.955 155.060 ;
    END
  END RBL[217]
  PIN RBL[218]
    ANTENNADIFFAREA 0.511400 ;
    PORT
      LAYER Metal4 ;
        RECT 7.045 155.430 19.065 156.430 ;
    END
  END RBL[218]
  PIN RBL[219]
    ANTENNADIFFAREA 0.511400 ;
    PORT
      LAYER Metal4 ;
        RECT 7.045 156.800 22.175 157.800 ;
    END
  END RBL[219]
  PIN RBL[220]
    ANTENNADIFFAREA 0.511400 ;
    PORT
      LAYER Metal4 ;
        RECT 25.005 156.800 37.380 157.800 ;
    END
  END RBL[220]
  PIN RBL[221]
    ANTENNADIFFAREA 0.511400 ;
    PORT
      LAYER Metal4 ;
        RECT 28.115 155.430 37.380 156.430 ;
    END
  END RBL[221]
  PIN RBL[222]
    ANTENNADIFFAREA 0.511400 ;
    PORT
      LAYER Metal4 ;
        RECT 31.225 154.060 37.380 155.060 ;
    END
  END RBL[222]
  PIN RBL[223]
    ANTENNADIFFAREA 0.511400 ;
    PORT
      LAYER Metal4 ;
        RECT 34.335 152.690 37.380 153.690 ;
    END
  END RBL[223]
  PIN RBL[224]
    ANTENNADIFFAREA 0.511400 ;
    PORT
      LAYER Metal4 ;
        RECT 7.045 158.170 12.555 159.170 ;
    END
  END RBL[224]
  PIN RBL[225]
    ANTENNADIFFAREA 0.511400 ;
    PORT
      LAYER Metal4 ;
        RECT 7.045 159.540 15.955 160.540 ;
    END
  END RBL[225]
  PIN RBL[226]
    ANTENNADIFFAREA 0.511400 ;
    PORT
      LAYER Metal4 ;
        RECT 7.045 160.910 19.065 161.910 ;
    END
  END RBL[226]
  PIN RBL[227]
    ANTENNADIFFAREA 0.511400 ;
    PORT
      LAYER Metal4 ;
        RECT 7.045 162.280 22.175 163.280 ;
    END
  END RBL[227]
  PIN RBL[228]
    ANTENNADIFFAREA 0.511400 ;
    PORT
      LAYER Metal4 ;
        RECT 25.005 162.280 37.380 163.280 ;
    END
  END RBL[228]
  PIN RBL[229]
    ANTENNADIFFAREA 0.511400 ;
    PORT
      LAYER Metal4 ;
        RECT 28.115 160.910 37.380 161.910 ;
    END
  END RBL[229]
  PIN RBL[230]
    ANTENNADIFFAREA 0.511400 ;
    PORT
      LAYER Metal4 ;
        RECT 31.225 159.540 37.380 160.540 ;
    END
  END RBL[230]
  PIN RBL[231]
    ANTENNADIFFAREA 0.511400 ;
    PORT
      LAYER Metal4 ;
        RECT 34.335 158.170 37.380 159.170 ;
    END
  END RBL[231]
  PIN RBL[232]
    ANTENNADIFFAREA 0.511400 ;
    PORT
      LAYER Metal4 ;
        RECT 7.045 163.650 12.555 164.650 ;
    END
  END RBL[232]
  PIN RBL[233]
    ANTENNADIFFAREA 0.511400 ;
    PORT
      LAYER Metal4 ;
        RECT 7.045 165.020 15.955 166.020 ;
    END
  END RBL[233]
  PIN RBL[234]
    ANTENNADIFFAREA 0.511400 ;
    PORT
      LAYER Metal4 ;
        RECT 7.045 166.390 19.065 167.390 ;
    END
  END RBL[234]
  PIN RBL[235]
    ANTENNADIFFAREA 0.511400 ;
    PORT
      LAYER Metal4 ;
        RECT 7.045 167.760 22.175 168.760 ;
    END
  END RBL[235]
  PIN RBL[236]
    ANTENNADIFFAREA 0.511400 ;
    PORT
      LAYER Metal4 ;
        RECT 25.005 167.760 37.380 168.760 ;
    END
  END RBL[236]
  PIN RBL[237]
    ANTENNADIFFAREA 0.511400 ;
    PORT
      LAYER Metal4 ;
        RECT 28.115 166.390 37.380 167.390 ;
    END
  END RBL[237]
  PIN RBL[238]
    ANTENNADIFFAREA 0.511400 ;
    PORT
      LAYER Metal4 ;
        RECT 31.225 165.020 37.380 166.020 ;
    END
  END RBL[238]
  PIN RBL[239]
    ANTENNADIFFAREA 0.511400 ;
    PORT
      LAYER Metal4 ;
        RECT 34.335 163.650 37.380 164.650 ;
    END
  END RBL[239]
  PIN RBL[240]
    ANTENNADIFFAREA 0.511400 ;
    PORT
      LAYER Metal4 ;
        RECT 7.045 169.130 12.555 170.130 ;
    END
  END RBL[240]
  PIN RBL[241]
    ANTENNADIFFAREA 0.511400 ;
    PORT
      LAYER Metal4 ;
        RECT 7.045 170.500 15.955 171.500 ;
    END
  END RBL[241]
  PIN RBL[242]
    ANTENNADIFFAREA 0.511400 ;
    PORT
      LAYER Metal4 ;
        RECT 7.045 171.870 19.065 172.870 ;
    END
  END RBL[242]
  PIN RBL[243]
    ANTENNADIFFAREA 0.511400 ;
    PORT
      LAYER Metal4 ;
        RECT 7.045 173.240 22.175 174.240 ;
    END
  END RBL[243]
  PIN RBL[244]
    ANTENNADIFFAREA 0.511400 ;
    PORT
      LAYER Metal4 ;
        RECT 25.005 173.240 37.380 174.240 ;
    END
  END RBL[244]
  PIN RBL[245]
    ANTENNADIFFAREA 0.511400 ;
    PORT
      LAYER Metal4 ;
        RECT 28.115 171.870 37.380 172.870 ;
    END
  END RBL[245]
  PIN RBL[246]
    ANTENNADIFFAREA 0.511400 ;
    PORT
      LAYER Metal4 ;
        RECT 31.225 170.500 37.380 171.500 ;
    END
  END RBL[246]
  PIN RBL[247]
    ANTENNADIFFAREA 0.511400 ;
    PORT
      LAYER Metal4 ;
        RECT 34.335 169.130 37.380 170.130 ;
    END
  END RBL[247]
  PIN RBL[248]
    ANTENNADIFFAREA 0.511400 ;
    PORT
      LAYER Metal4 ;
        RECT 7.045 174.610 12.555 175.610 ;
    END
  END RBL[248]
  PIN RBL[249]
    ANTENNADIFFAREA 0.511400 ;
    PORT
      LAYER Metal4 ;
        RECT 7.045 175.980 15.955 176.980 ;
    END
  END RBL[249]
  PIN RBL[250]
    ANTENNADIFFAREA 0.511400 ;
    PORT
      LAYER Metal4 ;
        RECT 7.045 177.350 19.065 178.350 ;
    END
  END RBL[250]
  PIN RBL[251]
    ANTENNADIFFAREA 0.511400 ;
    PORT
      LAYER Metal4 ;
        RECT 7.045 178.720 22.175 179.720 ;
    END
  END RBL[251]
  PIN RBL[252]
    ANTENNADIFFAREA 0.511400 ;
    PORT
      LAYER Metal4 ;
        RECT 25.005 178.720 37.380 179.720 ;
    END
  END RBL[252]
  PIN RBL[253]
    ANTENNADIFFAREA 0.511400 ;
    PORT
      LAYER Metal4 ;
        RECT 28.115 177.350 37.380 178.350 ;
    END
  END RBL[253]
  PIN RBL[254]
    ANTENNADIFFAREA 0.511400 ;
    PORT
      LAYER Metal4 ;
        RECT 31.225 175.980 37.380 176.980 ;
    END
  END RBL[254]
  PIN RBL[255]
    ANTENNADIFFAREA 0.511400 ;
    PORT
      LAYER Metal4 ;
        RECT 34.335 174.610 37.380 175.610 ;
    END
  END RBL[255]
  PIN VSS
    USE GROUND ;
    PORT
      LAYER Metal3 ;
        RECT 39.605 -1.150 40.750 182.900 ;
    END
  END VSS
  PIN WBL[0]
    ANTENNADIFFAREA 5.459200 ;
    PORT
      LAYER Metal3 ;
        RECT 11.375 180.525 12.335 181.215 ;
    END
  END WBL[0]
  PIN WBL[1]
    ANTENNADIFFAREA 5.459200 ;
    PORT
      LAYER Metal3 ;
        RECT 14.485 180.525 15.445 181.215 ;
    END
  END WBL[1]
  PIN WBL[2]
    ANTENNADIFFAREA 5.459200 ;
    PORT
      LAYER Metal3 ;
        RECT 17.595 180.525 18.555 181.215 ;
    END
  END WBL[2]
  PIN WBL[3]
    ANTENNADIFFAREA 5.459200 ;
    PORT
      LAYER Metal3 ;
        RECT 20.705 180.525 21.665 181.215 ;
    END
  END WBL[3]
  PIN WBL[4]
    ANTENNADIFFAREA 5.459200 ;
    PORT
      LAYER Metal3 ;
        RECT 23.815 180.525 24.775 181.215 ;
    END
  END WBL[4]
  PIN WBL[5]
    ANTENNADIFFAREA 5.459200 ;
    PORT
      LAYER Metal3 ;
        RECT 26.925 180.525 27.885 181.215 ;
    END
  END WBL[5]
  PIN WBL[6]
    ANTENNADIFFAREA 5.459200 ;
    PORT
      LAYER Metal3 ;
        RECT 30.035 180.525 30.995 181.215 ;
    END
  END WBL[6]
  PIN WBL[7]
    ANTENNADIFFAREA 5.459200 ;
    PORT
      LAYER Metal3 ;
        RECT 33.145 180.525 34.105 181.215 ;
    END
  END WBL[7]
  PIN WBLB[0]
    ANTENNADIFFAREA 7.558400 ;
    PORT
      LAYER Metal3 ;
        RECT 10.120 180.520 11.080 181.215 ;
    END
  END WBLB[0]
  PIN WBLB[1]
    ANTENNADIFFAREA 7.558400 ;
    PORT
      LAYER Metal3 ;
        RECT 13.230 180.520 14.190 181.215 ;
    END
  END WBLB[1]
  PIN WBLB[2]
    ANTENNADIFFAREA 7.558400 ;
    PORT
      LAYER Metal3 ;
        RECT 16.340 180.520 17.300 181.215 ;
    END
  END WBLB[2]
  PIN WBLB[3]
    ANTENNADIFFAREA 7.558400 ;
    PORT
      LAYER Metal3 ;
        RECT 19.450 180.520 20.410 181.215 ;
    END
  END WBLB[3]
  PIN WBLB[4]
    ANTENNADIFFAREA 7.558400 ;
    PORT
      LAYER Metal3 ;
        RECT 22.560 180.520 23.520 181.215 ;
    END
  END WBLB[4]
  PIN WBLB[5]
    ANTENNADIFFAREA 7.558400 ;
    PORT
      LAYER Metal3 ;
        RECT 25.670 180.520 26.630 181.215 ;
    END
  END WBLB[5]
  PIN WBLB[6]
    ANTENNADIFFAREA 7.558400 ;
    PORT
      LAYER Metal3 ;
        RECT 28.780 180.520 29.740 181.215 ;
    END
  END WBLB[6]
  PIN WBLB[7]
    ANTENNADIFFAREA 7.558400 ;
    PORT
      LAYER Metal3 ;
        RECT 31.890 180.520 32.850 181.215 ;
    END
  END WBLB[7]
  PIN WL[0]
    ANTENNAGATEAREA 1.433600 ;
    PORT
      LAYER Metal2 ;
        RECT 1.165 0.915 6.045 2.510 ;
    END
  END WL[0]
  PIN WL[1]
    ANTENNAGATEAREA 1.433600 ;
    PORT
      LAYER Metal2 ;
        RECT 1.165 6.395 6.045 7.990 ;
    END
  END WL[1]
  PIN WL[2]
    ANTENNAGATEAREA 1.433600 ;
    PORT
      LAYER Metal2 ;
        RECT 1.165 11.875 6.045 13.470 ;
    END
  END WL[2]
  PIN WL[3]
    ANTENNAGATEAREA 1.433600 ;
    PORT
      LAYER Metal2 ;
        RECT 1.165 17.355 6.045 18.950 ;
    END
  END WL[3]
  PIN WL[4]
    ANTENNAGATEAREA 1.433600 ;
    PORT
      LAYER Metal2 ;
        RECT 1.165 22.835 6.045 24.430 ;
    END
  END WL[4]
  PIN WL[5]
    ANTENNAGATEAREA 1.433600 ;
    PORT
      LAYER Metal2 ;
        RECT 1.165 28.315 6.045 29.910 ;
    END
  END WL[5]
  PIN WL[6]
    ANTENNAGATEAREA 1.433600 ;
    PORT
      LAYER Metal2 ;
        RECT 1.165 33.795 6.045 35.390 ;
    END
  END WL[6]
  PIN WL[7]
    ANTENNAGATEAREA 1.433600 ;
    PORT
      LAYER Metal2 ;
        RECT 1.165 39.275 6.045 40.870 ;
    END
  END WL[7]
  PIN WL[8]
    ANTENNAGATEAREA 1.433600 ;
    PORT
      LAYER Metal2 ;
        RECT 1.165 44.755 6.045 46.350 ;
    END
  END WL[8]
  PIN WL[9]
    ANTENNAGATEAREA 1.433600 ;
    PORT
      LAYER Metal2 ;
        RECT 1.165 50.235 6.045 51.830 ;
    END
  END WL[9]
  PIN WL[10]
    ANTENNAGATEAREA 1.433600 ;
    PORT
      LAYER Metal2 ;
        RECT 1.165 55.715 6.045 57.310 ;
    END
  END WL[10]
  PIN WL[11]
    ANTENNAGATEAREA 1.433600 ;
    PORT
      LAYER Metal2 ;
        RECT 1.165 61.195 6.045 62.790 ;
    END
  END WL[11]
  PIN WL[12]
    ANTENNAGATEAREA 1.433600 ;
    PORT
      LAYER Metal2 ;
        RECT 1.165 66.675 6.045 68.270 ;
    END
  END WL[12]
  PIN WL[13]
    ANTENNAGATEAREA 1.433600 ;
    PORT
      LAYER Metal2 ;
        RECT 1.165 72.155 6.045 73.750 ;
    END
  END WL[13]
  PIN WL[14]
    ANTENNAGATEAREA 1.433600 ;
    PORT
      LAYER Metal2 ;
        RECT 1.165 77.635 6.045 79.230 ;
    END
  END WL[14]
  PIN WL[15]
    ANTENNAGATEAREA 1.433600 ;
    PORT
      LAYER Metal2 ;
        RECT 1.165 83.115 6.045 84.710 ;
    END
  END WL[15]
  PIN WL[16]
    ANTENNAGATEAREA 1.433600 ;
    PORT
      LAYER Metal2 ;
        RECT 1.165 88.595 6.045 90.190 ;
    END
  END WL[16]
  PIN WL[17]
    ANTENNAGATEAREA 1.433600 ;
    PORT
      LAYER Metal2 ;
        RECT 1.165 94.075 6.045 95.670 ;
    END
  END WL[17]
  PIN WL[18]
    ANTENNAGATEAREA 1.433600 ;
    PORT
      LAYER Metal2 ;
        RECT 1.165 99.555 6.045 101.150 ;
    END
  END WL[18]
  PIN WL[19]
    ANTENNAGATEAREA 1.433600 ;
    PORT
      LAYER Metal2 ;
        RECT 1.165 105.035 6.045 106.630 ;
    END
  END WL[19]
  PIN WL[20]
    ANTENNAGATEAREA 1.433600 ;
    PORT
      LAYER Metal2 ;
        RECT 1.165 110.515 6.045 112.110 ;
    END
  END WL[20]
  PIN WL[21]
    ANTENNAGATEAREA 1.433600 ;
    PORT
      LAYER Metal2 ;
        RECT 1.165 115.995 6.045 117.590 ;
    END
  END WL[21]
  PIN WL[22]
    ANTENNAGATEAREA 1.433600 ;
    PORT
      LAYER Metal2 ;
        RECT 1.165 121.475 6.045 123.070 ;
    END
  END WL[22]
  PIN WL[23]
    ANTENNAGATEAREA 1.433600 ;
    PORT
      LAYER Metal2 ;
        RECT 1.165 126.955 6.045 128.550 ;
    END
  END WL[23]
  PIN WL[24]
    ANTENNAGATEAREA 1.433600 ;
    PORT
      LAYER Metal2 ;
        RECT 1.165 132.435 6.045 134.030 ;
    END
  END WL[24]
  PIN WL[25]
    ANTENNAGATEAREA 1.433600 ;
    PORT
      LAYER Metal2 ;
        RECT 1.165 137.915 6.045 139.510 ;
    END
  END WL[25]
  PIN WL[26]
    ANTENNAGATEAREA 1.433600 ;
    PORT
      LAYER Metal2 ;
        RECT 1.165 143.395 6.045 144.990 ;
    END
  END WL[26]
  PIN WL[27]
    ANTENNAGATEAREA 1.433600 ;
    PORT
      LAYER Metal2 ;
        RECT 1.165 148.875 6.045 150.470 ;
    END
  END WL[27]
  PIN WL[28]
    ANTENNAGATEAREA 1.433600 ;
    PORT
      LAYER Metal2 ;
        RECT 1.165 154.355 6.045 155.950 ;
    END
  END WL[28]
  PIN WL[29]
    ANTENNAGATEAREA 1.433600 ;
    PORT
      LAYER Metal2 ;
        RECT 1.165 159.835 6.045 161.430 ;
    END
  END WL[29]
  PIN WL[30]
    ANTENNAGATEAREA 1.433600 ;
    PORT
      LAYER Metal2 ;
        RECT 1.165 165.315 6.045 166.910 ;
    END
  END WL[30]
  PIN WL[31]
    ANTENNAGATEAREA 1.433600 ;
    PORT
      LAYER Metal2 ;
        RECT 1.165 170.795 6.045 172.390 ;
    END
  END WL[31]
  PIN VDD
    USE POWER ;
    PORT
      LAYER Metal2 ;
        RECT 4.800 -1.305 37.595 -0.025 ;
    END
  END VDD
  OBS
      LAYER Nwell ;
        RECT 8.425 1.270 36.145 176.630 ;
      LAYER Metal1 ;
        RECT 4.085 -1.030 40.745 182.590 ;
      LAYER Metal2 ;
        RECT 3.885 176.595 41.420 177.185 ;
        RECT 3.885 174.400 41.120 176.595 ;
        RECT 3.885 172.690 41.420 174.400 ;
        RECT 6.345 171.115 41.420 172.690 ;
        RECT 6.345 170.495 41.120 171.115 ;
        RECT 3.885 168.920 41.120 170.495 ;
        RECT 3.885 167.210 41.420 168.920 ;
        RECT 6.345 165.635 41.420 167.210 ;
        RECT 6.345 165.015 41.120 165.635 ;
        RECT 3.885 163.440 41.120 165.015 ;
        RECT 3.885 161.730 41.420 163.440 ;
        RECT 6.345 160.155 41.420 161.730 ;
        RECT 6.345 159.535 41.120 160.155 ;
        RECT 3.885 157.960 41.120 159.535 ;
        RECT 3.885 156.250 41.420 157.960 ;
        RECT 6.345 154.675 41.420 156.250 ;
        RECT 6.345 154.055 41.120 154.675 ;
        RECT 3.885 152.480 41.120 154.055 ;
        RECT 3.885 150.770 41.420 152.480 ;
        RECT 6.345 149.195 41.420 150.770 ;
        RECT 6.345 148.575 41.120 149.195 ;
        RECT 3.885 147.000 41.120 148.575 ;
        RECT 3.885 145.290 41.420 147.000 ;
        RECT 6.345 143.715 41.420 145.290 ;
        RECT 6.345 143.095 41.120 143.715 ;
        RECT 3.885 141.520 41.120 143.095 ;
        RECT 3.885 139.810 41.420 141.520 ;
        RECT 6.345 138.235 41.420 139.810 ;
        RECT 6.345 137.615 41.120 138.235 ;
        RECT 3.885 136.040 41.120 137.615 ;
        RECT 3.885 134.330 41.420 136.040 ;
        RECT 6.345 132.755 41.420 134.330 ;
        RECT 6.345 132.135 41.120 132.755 ;
        RECT 3.885 130.560 41.120 132.135 ;
        RECT 3.885 128.850 41.420 130.560 ;
        RECT 6.345 127.275 41.420 128.850 ;
        RECT 6.345 126.655 41.120 127.275 ;
        RECT 3.885 125.080 41.120 126.655 ;
        RECT 3.885 123.370 41.420 125.080 ;
        RECT 6.345 121.795 41.420 123.370 ;
        RECT 6.345 121.175 41.120 121.795 ;
        RECT 3.885 119.600 41.120 121.175 ;
        RECT 3.885 117.890 41.420 119.600 ;
        RECT 6.345 116.315 41.420 117.890 ;
        RECT 6.345 115.695 41.120 116.315 ;
        RECT 3.885 114.120 41.120 115.695 ;
        RECT 3.885 112.410 41.420 114.120 ;
        RECT 6.345 110.835 41.420 112.410 ;
        RECT 6.345 110.215 41.120 110.835 ;
        RECT 3.885 108.640 41.120 110.215 ;
        RECT 3.885 106.930 41.420 108.640 ;
        RECT 6.345 105.355 41.420 106.930 ;
        RECT 6.345 104.735 41.120 105.355 ;
        RECT 3.885 103.160 41.120 104.735 ;
        RECT 3.885 101.450 41.420 103.160 ;
        RECT 6.345 99.875 41.420 101.450 ;
        RECT 6.345 99.255 41.120 99.875 ;
        RECT 3.885 97.680 41.120 99.255 ;
        RECT 3.885 95.970 41.420 97.680 ;
        RECT 6.345 94.395 41.420 95.970 ;
        RECT 6.345 93.775 41.120 94.395 ;
        RECT 3.885 92.200 41.120 93.775 ;
        RECT 3.885 90.490 41.420 92.200 ;
        RECT 6.345 88.915 41.420 90.490 ;
        RECT 6.345 88.295 41.120 88.915 ;
        RECT 3.885 86.720 41.120 88.295 ;
        RECT 3.885 85.010 41.420 86.720 ;
        RECT 6.345 83.435 41.420 85.010 ;
        RECT 6.345 82.815 41.120 83.435 ;
        RECT 3.885 81.240 41.120 82.815 ;
        RECT 3.885 79.530 41.420 81.240 ;
        RECT 6.345 77.955 41.420 79.530 ;
        RECT 6.345 77.335 41.120 77.955 ;
        RECT 3.885 75.760 41.120 77.335 ;
        RECT 3.885 74.050 41.420 75.760 ;
        RECT 6.345 72.475 41.420 74.050 ;
        RECT 6.345 71.855 41.120 72.475 ;
        RECT 3.885 70.280 41.120 71.855 ;
        RECT 3.885 68.570 41.420 70.280 ;
        RECT 6.345 66.995 41.420 68.570 ;
        RECT 6.345 66.375 41.120 66.995 ;
        RECT 3.885 64.800 41.120 66.375 ;
        RECT 3.885 63.090 41.420 64.800 ;
        RECT 6.345 61.515 41.420 63.090 ;
        RECT 6.345 60.895 41.120 61.515 ;
        RECT 3.885 59.320 41.120 60.895 ;
        RECT 3.885 57.610 41.420 59.320 ;
        RECT 6.345 56.035 41.420 57.610 ;
        RECT 6.345 55.415 41.120 56.035 ;
        RECT 3.885 53.840 41.120 55.415 ;
        RECT 3.885 52.130 41.420 53.840 ;
        RECT 6.345 50.555 41.420 52.130 ;
        RECT 6.345 49.935 41.120 50.555 ;
        RECT 3.885 48.360 41.120 49.935 ;
        RECT 3.885 46.650 41.420 48.360 ;
        RECT 6.345 45.075 41.420 46.650 ;
        RECT 6.345 44.455 41.120 45.075 ;
        RECT 3.885 42.880 41.120 44.455 ;
        RECT 3.885 41.170 41.420 42.880 ;
        RECT 6.345 39.595 41.420 41.170 ;
        RECT 6.345 38.975 41.120 39.595 ;
        RECT 3.885 37.400 41.120 38.975 ;
        RECT 3.885 35.690 41.420 37.400 ;
        RECT 6.345 34.115 41.420 35.690 ;
        RECT 6.345 33.495 41.120 34.115 ;
        RECT 3.885 31.920 41.120 33.495 ;
        RECT 3.885 30.210 41.420 31.920 ;
        RECT 6.345 28.635 41.420 30.210 ;
        RECT 6.345 28.015 41.120 28.635 ;
        RECT 3.885 26.440 41.120 28.015 ;
        RECT 3.885 24.730 41.420 26.440 ;
        RECT 6.345 23.155 41.420 24.730 ;
        RECT 6.345 22.535 41.120 23.155 ;
        RECT 3.885 20.960 41.120 22.535 ;
        RECT 3.885 19.250 41.420 20.960 ;
        RECT 6.345 17.675 41.420 19.250 ;
        RECT 6.345 17.055 41.120 17.675 ;
        RECT 3.885 15.480 41.120 17.055 ;
        RECT 3.885 13.770 41.420 15.480 ;
        RECT 6.345 12.195 41.420 13.770 ;
        RECT 6.345 11.575 41.120 12.195 ;
        RECT 3.885 10.000 41.120 11.575 ;
        RECT 3.885 8.290 41.420 10.000 ;
        RECT 6.345 6.715 41.420 8.290 ;
        RECT 6.345 6.095 41.120 6.715 ;
        RECT 3.885 4.520 41.120 6.095 ;
        RECT 3.885 2.810 41.420 4.520 ;
        RECT 6.345 0.615 41.420 2.810 ;
        RECT 3.885 0.275 41.420 0.615 ;
        RECT 3.885 -1.305 4.500 0.275 ;
        RECT 37.895 -1.305 41.420 0.275 ;
      LAYER Metal3 ;
        RECT 12.635 180.225 12.930 180.525 ;
        RECT 15.745 180.225 16.040 180.525 ;
        RECT 18.855 180.225 19.150 180.525 ;
        RECT 21.965 180.225 22.260 180.525 ;
        RECT 25.075 180.225 25.370 180.525 ;
        RECT 28.185 180.225 28.480 180.525 ;
        RECT 31.295 180.225 31.590 180.525 ;
        RECT 34.405 180.225 39.305 180.525 ;
        RECT 11.380 180.220 12.930 180.225 ;
        RECT 14.490 180.220 16.040 180.225 ;
        RECT 17.600 180.220 19.150 180.225 ;
        RECT 20.710 180.220 22.260 180.225 ;
        RECT 23.820 180.220 25.370 180.225 ;
        RECT 26.930 180.220 28.480 180.225 ;
        RECT 30.040 180.220 31.590 180.225 ;
        RECT 33.150 180.220 39.305 180.225 ;
        RECT 10.365 1.270 39.305 180.220 ;
      LAYER Metal4 ;
        RECT 22.475 178.420 24.705 178.720 ;
        RECT 19.365 177.050 27.815 178.420 ;
        RECT 16.255 175.680 30.925 177.050 ;
        RECT 12.855 174.540 32.225 175.680 ;
        RECT 22.475 172.940 24.705 174.540 ;
        RECT 19.365 171.570 27.815 172.940 ;
        RECT 16.255 170.200 30.925 171.570 ;
        RECT 12.855 169.060 32.225 170.200 ;
        RECT 22.475 167.460 24.705 169.060 ;
        RECT 19.365 166.090 27.815 167.460 ;
        RECT 16.255 164.720 30.925 166.090 ;
        RECT 12.855 163.580 32.225 164.720 ;
        RECT 22.475 161.980 24.705 163.580 ;
        RECT 19.365 160.610 27.815 161.980 ;
        RECT 16.255 159.240 30.925 160.610 ;
        RECT 12.855 158.100 32.225 159.240 ;
        RECT 22.475 156.500 24.705 158.100 ;
        RECT 19.365 155.130 27.815 156.500 ;
        RECT 16.255 153.760 30.925 155.130 ;
        RECT 12.855 152.620 32.225 153.760 ;
        RECT 22.475 151.020 24.705 152.620 ;
        RECT 19.365 149.650 27.815 151.020 ;
        RECT 16.255 148.280 30.925 149.650 ;
        RECT 12.855 147.140 32.225 148.280 ;
        RECT 22.475 145.540 24.705 147.140 ;
        RECT 19.365 144.170 27.815 145.540 ;
        RECT 16.255 142.800 30.925 144.170 ;
        RECT 12.855 141.660 32.225 142.800 ;
        RECT 22.475 140.060 24.705 141.660 ;
        RECT 19.365 138.690 27.815 140.060 ;
        RECT 16.255 137.320 30.925 138.690 ;
        RECT 12.855 136.180 32.225 137.320 ;
        RECT 22.475 134.580 24.705 136.180 ;
        RECT 19.365 133.210 27.815 134.580 ;
        RECT 16.255 131.840 30.925 133.210 ;
        RECT 12.855 130.700 32.225 131.840 ;
        RECT 22.475 129.100 24.705 130.700 ;
        RECT 19.365 127.730 27.815 129.100 ;
        RECT 16.255 126.360 30.925 127.730 ;
        RECT 12.855 125.220 32.225 126.360 ;
        RECT 22.475 123.620 24.705 125.220 ;
        RECT 19.365 122.250 27.815 123.620 ;
        RECT 16.255 120.880 30.925 122.250 ;
        RECT 12.855 119.740 32.225 120.880 ;
        RECT 22.475 118.140 24.705 119.740 ;
        RECT 19.365 116.770 27.815 118.140 ;
        RECT 16.255 115.400 30.925 116.770 ;
        RECT 12.855 114.260 32.225 115.400 ;
        RECT 22.475 112.660 24.705 114.260 ;
        RECT 19.365 111.290 27.815 112.660 ;
        RECT 16.255 109.920 30.925 111.290 ;
        RECT 12.855 108.780 32.225 109.920 ;
        RECT 22.475 107.180 24.705 108.780 ;
        RECT 19.365 105.810 27.815 107.180 ;
        RECT 16.255 104.440 30.925 105.810 ;
        RECT 12.855 103.300 32.225 104.440 ;
        RECT 22.475 101.700 24.705 103.300 ;
        RECT 19.365 100.330 27.815 101.700 ;
        RECT 16.255 98.960 30.925 100.330 ;
        RECT 12.855 97.820 32.225 98.960 ;
        RECT 22.475 96.220 24.705 97.820 ;
        RECT 19.365 94.850 27.815 96.220 ;
        RECT 16.255 93.480 30.925 94.850 ;
        RECT 12.855 92.340 32.225 93.480 ;
        RECT 22.475 90.740 24.705 92.340 ;
        RECT 19.365 89.370 27.815 90.740 ;
        RECT 16.255 88.000 30.925 89.370 ;
        RECT 12.855 86.860 32.225 88.000 ;
        RECT 22.475 85.260 24.705 86.860 ;
        RECT 19.365 83.890 27.815 85.260 ;
        RECT 16.255 82.520 30.925 83.890 ;
        RECT 12.855 81.380 32.225 82.520 ;
        RECT 22.475 79.780 24.705 81.380 ;
        RECT 19.365 78.410 27.815 79.780 ;
        RECT 16.255 77.040 30.925 78.410 ;
        RECT 12.855 75.900 32.225 77.040 ;
        RECT 22.475 74.300 24.705 75.900 ;
        RECT 19.365 72.930 27.815 74.300 ;
        RECT 16.255 71.560 30.925 72.930 ;
        RECT 12.855 70.420 32.225 71.560 ;
        RECT 22.475 68.820 24.705 70.420 ;
        RECT 19.365 67.450 27.815 68.820 ;
        RECT 16.255 66.080 30.925 67.450 ;
        RECT 12.855 64.940 32.225 66.080 ;
        RECT 22.475 63.340 24.705 64.940 ;
        RECT 19.365 61.970 27.815 63.340 ;
        RECT 16.255 60.600 30.925 61.970 ;
        RECT 12.855 59.460 32.225 60.600 ;
        RECT 22.475 57.860 24.705 59.460 ;
        RECT 19.365 56.490 27.815 57.860 ;
        RECT 16.255 55.120 30.925 56.490 ;
        RECT 12.855 53.980 32.225 55.120 ;
        RECT 22.475 52.380 24.705 53.980 ;
        RECT 19.365 51.010 27.815 52.380 ;
        RECT 16.255 49.640 30.925 51.010 ;
        RECT 12.855 48.500 32.225 49.640 ;
        RECT 22.475 46.900 24.705 48.500 ;
        RECT 19.365 45.530 27.815 46.900 ;
        RECT 16.255 44.160 30.925 45.530 ;
        RECT 12.855 43.020 32.225 44.160 ;
        RECT 22.475 41.420 24.705 43.020 ;
        RECT 19.365 40.050 27.815 41.420 ;
        RECT 16.255 38.680 30.925 40.050 ;
        RECT 12.855 37.540 32.225 38.680 ;
        RECT 22.475 35.940 24.705 37.540 ;
        RECT 19.365 34.570 27.815 35.940 ;
        RECT 16.255 33.200 30.925 34.570 ;
        RECT 12.855 32.060 32.225 33.200 ;
        RECT 22.475 30.460 24.705 32.060 ;
        RECT 19.365 29.090 27.815 30.460 ;
        RECT 16.255 27.720 30.925 29.090 ;
        RECT 12.855 26.580 32.225 27.720 ;
        RECT 22.475 24.980 24.705 26.580 ;
        RECT 19.365 23.610 27.815 24.980 ;
        RECT 16.255 22.240 30.925 23.610 ;
        RECT 12.855 21.100 32.225 22.240 ;
        RECT 22.475 19.500 24.705 21.100 ;
        RECT 19.365 18.130 27.815 19.500 ;
        RECT 16.255 16.760 30.925 18.130 ;
        RECT 12.855 15.620 32.225 16.760 ;
        RECT 22.475 14.020 24.705 15.620 ;
        RECT 19.365 12.650 27.815 14.020 ;
        RECT 16.255 11.280 30.925 12.650 ;
        RECT 12.855 10.140 32.225 11.280 ;
        RECT 22.475 8.540 24.705 10.140 ;
        RECT 19.365 7.170 27.815 8.540 ;
        RECT 16.255 5.800 30.925 7.170 ;
        RECT 12.855 4.730 32.225 5.800 ;
  END
END sram_32x8_9T
END LIBRARY

